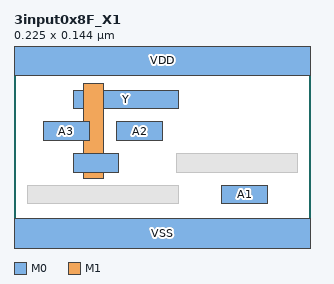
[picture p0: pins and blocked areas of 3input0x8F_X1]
MACRO 3input0x8F_X1
  CLASS CORE ;
  ORIGIN 0 0 ;
  FOREIGN 3input0x8F_X1 0 0 ;
  SIZE 0.2250 BY 0.1440 ;
  SYMMETRY X Y ;
  SITE coresite ;
  PIN A1
    DIRECTION INPUT ;
    USE SIGNAL ;
    PORT
      LAYER M0 ;
        RECT 0.1575 0.0290 0.1920 0.0430 ;
    END
  END A1
  PIN A2
    DIRECTION INPUT ;
    USE SIGNAL ;
    PORT
      LAYER M0 ;
        RECT 0.0780 0.0770 0.1125 0.0910 ;
    END
  END A2
  PIN A3
    DIRECTION INPUT ;
    USE SIGNAL ;
    PORT
      LAYER M0 ;
        RECT 0.0225 0.0770 0.0570 0.0910 ;
    END
  END A3
  PIN Y
    DIRECTION OUTPUT ;
    USE SIGNAL ;
    PORT
      LAYER M1 ;
        RECT 0.0525 0.0480 0.0675 0.1200 ;
      LAYER M0 ;
        RECT 0.0450 0.1010 0.1245 0.1150 ;
        RECT 0.0450 0.0530 0.0795 0.0670 ;
    END
  END Y
  PIN VDD
    DIRECTION INOUT ;
    USE POWER ;
    SHAPE ABUTMENT ;
    PORT
      LAYER M0 ;
        RECT 0.0000 0.1260 0.2250 0.1620 ;
    END
  END VDD
  PIN VSS
    DIRECTION INOUT ;
    USE GROUND ;
    SHAPE ABUTMENT ;
    PORT
      LAYER M0 ;
        RECT 0.0000 -0.0180 0.2250 0.0180 ;
    END
  END VSS
  OBS
    LAYER V0 ;
      RECT 0.0530 0.1010 0.0670 0.1150 ;
      RECT 0.0530 0.0530 0.0670 0.0670 ;
    LAYER M0 ;
      RECT 0.0105 0.0290 0.1245 0.0430 ;
      RECT 0.1230 0.0530 0.2145 0.0670 ;
  END
END 3input0x8F_X1
